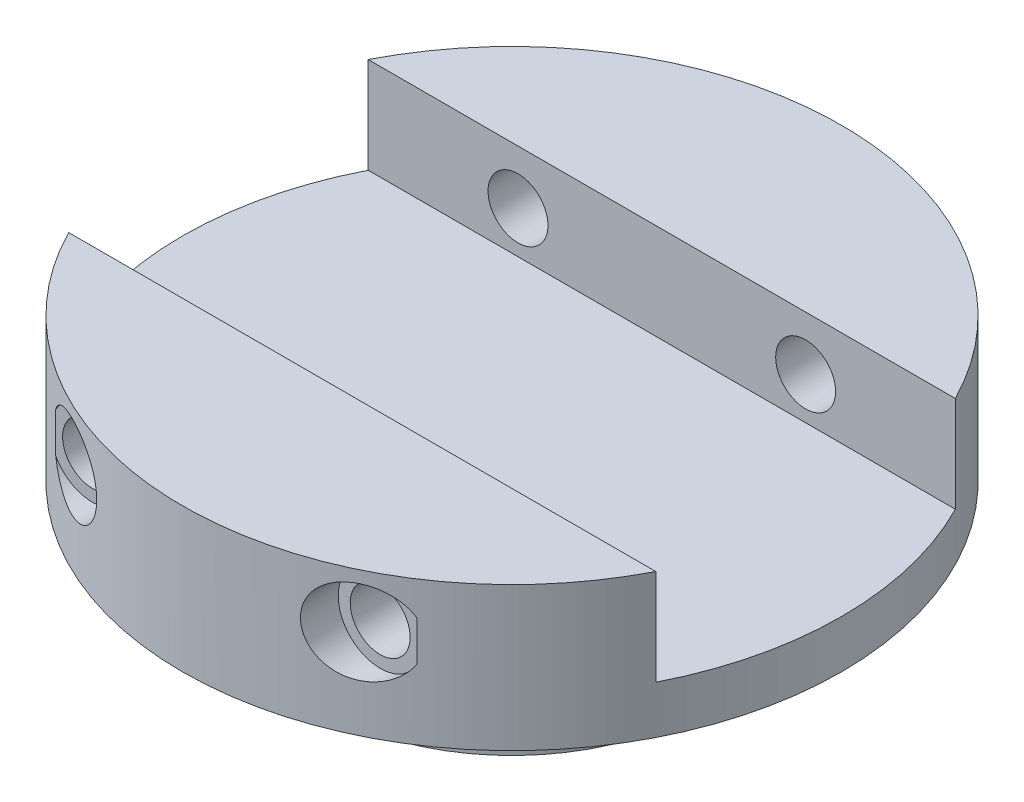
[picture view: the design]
ISO-10303-21;
HEADER;
FILE_DESCRIPTION(('STEP AP214'),'2;1');
FILE_NAME('part.step','',(''),(''),'','','');
FILE_SCHEMA(('AUTOMOTIVE_DESIGN { 1 0 10303 214 1 1 1 1 }'));
ENDSEC;
DATA;
#1=APPLICATION_CONTEXT('core data for automotive mechanical design processes');
#2=APPLICATION_PROTOCOL_DEFINITION('international standard','automotive_design',2000,#1);
#3=PRODUCT_CONTEXT('',#1,'mechanical');
#4=PRODUCT('Part','Part','',(#3));
#5=PRODUCT_RELATED_PRODUCT_CATEGORY('part','',(#4));
#6=PRODUCT_DEFINITION_FORMATION('','',#4);
#7=PRODUCT_DEFINITION_CONTEXT('part definition',#1,'design');
#8=PRODUCT_DEFINITION('design','',#6,#7);
#9=PRODUCT_DEFINITION_SHAPE('','',#8);
#10=(LENGTH_UNIT() NAMED_UNIT(*) SI_UNIT(.MILLI.,.METRE.));
#11=(NAMED_UNIT(*) PLANE_ANGLE_UNIT() SI_UNIT($,.RADIAN.));
#12=(NAMED_UNIT(*) SI_UNIT($,.STERADIAN.) SOLID_ANGLE_UNIT());
#13=UNCERTAINTY_MEASURE_WITH_UNIT(LENGTH_MEASURE(1.E-05),#10,'distance_accuracy_value','');
#14=(GEOMETRIC_REPRESENTATION_CONTEXT(3) GLOBAL_UNCERTAINTY_ASSIGNED_CONTEXT((#13)) GLOBAL_UNIT_ASSIGNED_CONTEXT((#10,
#11,#12)) REPRESENTATION_CONTEXT('',''));
#15=CARTESIAN_POINT('',(0.,0.,0.));
#16=DIRECTION('',(0.,0.,1.));
#17=DIRECTION('',(1.,0.,0.));
#18=AXIS2_PLACEMENT_3D('',#15,#16,#17);
#19=CARTESIAN_POINT('',(0.,19.05,0.));
#20=DIRECTION('',(0.,-1.,0.));
#21=DIRECTION('',(0.,0.,-1.));
#22=AXIS2_PLACEMENT_3D('',#19,#20,#21);
#23=CYLINDRICAL_SURFACE('',#22,43.65625);
#24=DIRECTION('',(0.,-1.,0.));
#25=VECTOR('',#24,1.);
#26=CARTESIAN_POINT('',(-23.9312663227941,19.05,-36.5125));
#27=LINE('',#26,#25);
#28=CARTESIAN_POINT('',(-23.9312663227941,9.25197926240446,-36.5125));
#29=VERTEX_POINT('',#28);
#30=CARTESIAN_POINT('',(-23.9312663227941,14.5605207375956,-36.5125));
#31=VERTEX_POINT('',#30);
#32=EDGE_CURVE('E121',#29,#31,#27,.F.);
#33=ORIENTED_EDGE('',*,*,#32,.F.);
#34=CARTESIAN_POINT('',(-23.9312663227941,9.25197926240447,-36.5125));
#35=CARTESIAN_POINT('',(-23.852149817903,9.10649225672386,-36.5643550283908));
#36=CARTESIAN_POINT('',(-23.7671347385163,8.96563827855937,-36.6197081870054));
#37=CARTESIAN_POINT('',(-23.5863859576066,8.69381280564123,-36.7363872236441));
#38=CARTESIAN_POINT('',(-23.4906623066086,8.56283223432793,-36.7977074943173));
#39=CARTESIAN_POINT('',(-23.1898679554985,8.18655993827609,-36.9885676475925));
#40=CARTESIAN_POINT('',(-22.9703170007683,7.9563920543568,-37.1255750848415));
#41=CARTESIAN_POINT('',(-22.5013637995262,7.54070185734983,-37.4116565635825));
#42=CARTESIAN_POINT('',(-22.2520689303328,7.35502581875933,-37.5606866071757));
#43=CARTESIAN_POINT('',(-21.7288893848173,7.02868923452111,-37.8657541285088));
#44=CARTESIAN_POINT('',(-21.4549682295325,6.88809692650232,-38.0218018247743));
#45=CARTESIAN_POINT('',(-20.8574448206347,6.64119424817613,-38.3531522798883));
#46=CARTESIAN_POINT('',(-20.5316948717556,6.54037308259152,-38.528680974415));
#47=CARTESIAN_POINT('',(-19.8653398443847,6.3996254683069,-38.8764367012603));
#48=CARTESIAN_POINT('',(-19.5247345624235,6.35969985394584,-39.0486636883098));
#49=CARTESIAN_POINT('',(-19.0052198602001,6.34737392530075,-39.3027821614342));
#50=CARTESIAN_POINT('',(-18.8281730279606,6.35158706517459,-39.3878986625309));
#51=CARTESIAN_POINT('',(-18.4739793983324,6.3770915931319,-39.5552586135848));
#52=CARTESIAN_POINT('',(-18.2968326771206,6.39837560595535,-39.6375032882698));
#53=CARTESIAN_POINT('',(-17.9438463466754,6.45827747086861,-39.7985454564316));
#54=CARTESIAN_POINT('',(-17.7680071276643,6.49690030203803,-39.8773419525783));
#55=CARTESIAN_POINT('',(-17.4193685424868,6.5915950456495,-40.0308631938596));
#56=CARTESIAN_POINT('',(-17.2465676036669,6.64765763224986,-40.1055900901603));
#57=CARTESIAN_POINT('',(-16.9162416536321,6.77319605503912,-40.2459827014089));
#58=CARTESIAN_POINT('',(-16.7584344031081,6.84162271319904,-40.3119229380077));
#59=CARTESIAN_POINT('',(-16.448512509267,6.99361875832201,-40.4393701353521));
#60=CARTESIAN_POINT('',(-16.2963950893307,7.07718063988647,-40.5008792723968));
#61=CARTESIAN_POINT('',(-15.9993741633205,7.25910905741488,-40.6191302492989));
#62=CARTESIAN_POINT('',(-15.8544689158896,7.35747199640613,-40.6758732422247));
#63=CARTESIAN_POINT('',(-15.5734291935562,7.56848128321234,-40.7843003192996));
#64=CARTESIAN_POINT('',(-15.4372939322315,7.68112634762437,-40.8359848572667));
#65=CARTESIAN_POINT('',(-15.1871935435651,7.90917059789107,-40.9296165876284));
#66=CARTESIAN_POINT('',(-15.0723362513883,8.02340507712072,-40.97202157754));
#67=CARTESIAN_POINT('',(-14.8523466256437,8.26235285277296,-41.052279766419));
#68=CARTESIAN_POINT('',(-14.7472134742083,8.38706526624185,-41.0901333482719));
#69=CARTESIAN_POINT('',(-14.547798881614,8.64606537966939,-41.1611578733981));
#70=CARTESIAN_POINT('',(-14.4535140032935,8.78035002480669,-41.1943303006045));
#71=CARTESIAN_POINT('',(-14.2767751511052,9.0575223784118,-41.2559161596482));
#72=CARTESIAN_POINT('',(-14.1943206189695,9.20040968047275,-41.2843298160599));
#73=CARTESIAN_POINT('',(-14.0473575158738,9.48361362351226,-41.3345560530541));
#74=CARTESIAN_POINT('',(-13.9820072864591,9.6234377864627,-41.3566871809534));
#75=CARTESIAN_POINT('',(-13.8629979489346,9.90855539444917,-41.3967317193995));
#76=CARTESIAN_POINT('',(-13.8093381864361,10.0538485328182,-41.4146453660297));
#77=CARTESIAN_POINT('',(-13.7142455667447,10.3488016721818,-41.4462319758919));
#78=CARTESIAN_POINT('',(-13.6728104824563,10.4984608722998,-41.4599057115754));
#79=CARTESIAN_POINT('',(-13.6025661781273,10.8010357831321,-41.4830052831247));
#80=CARTESIAN_POINT('',(-13.5737567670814,10.9539514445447,-41.4924311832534));
#81=CARTESIAN_POINT('',(-13.5298518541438,11.2563426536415,-41.5067679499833));
#82=CARTESIAN_POINT('',(-13.5143023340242,11.4057453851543,-41.5118283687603));
#83=CARTESIAN_POINT('',(-13.4953490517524,11.7054530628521,-41.5179939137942));
#84=CARTESIAN_POINT('',(-13.4919493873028,11.8557582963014,-41.5190977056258));
#85=CARTESIAN_POINT('',(-13.4973382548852,12.1560584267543,-41.5173461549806));
#86=CARTESIAN_POINT('',(-13.50612128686,12.3060534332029,-41.5144925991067));
#87=CARTESIAN_POINT('',(-13.5357892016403,12.604769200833,-41.5048288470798));
#88=CARTESIAN_POINT('',(-13.5566785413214,12.7534894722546,-41.4980171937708));
#89=CARTESIAN_POINT('',(-13.6100836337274,13.0469666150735,-41.4805323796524));
#90=CARTESIAN_POINT('',(-13.6424742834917,13.1917487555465,-41.4699007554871));
#91=CARTESIAN_POINT('',(-13.7186346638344,13.4780008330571,-41.4447684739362));
#92=CARTESIAN_POINT('',(-13.7624085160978,13.6194695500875,-41.4302664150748));
#93=CARTESIAN_POINT('',(-13.8609149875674,13.8980143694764,-41.3974140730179));
#94=CARTESIAN_POINT('',(-13.9156433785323,14.0350921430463,-41.3790652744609));
#95=CARTESIAN_POINT('',(-14.0356017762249,14.3040436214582,-41.3385298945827));
#96=CARTESIAN_POINT('',(-14.1008356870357,14.4359153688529,-41.3163418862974));
#97=CARTESIAN_POINT('',(-14.2419201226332,14.694840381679,-41.2679232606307));
#98=CARTESIAN_POINT('',(-14.3178707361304,14.821831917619,-41.2416542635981));
#99=CARTESIAN_POINT('',(-14.4792383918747,15.0688156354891,-41.1852779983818));
#100=CARTESIAN_POINT('',(-14.5646588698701,15.188805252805,-41.1551693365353));
#101=CARTESIAN_POINT('',(-14.7441756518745,15.420978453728,-41.091197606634));
#102=CARTESIAN_POINT('',(-14.8382692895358,15.5331644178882,-41.0573356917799));
#103=CARTESIAN_POINT('',(-15.034393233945,15.749179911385,-40.9859253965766));
#104=CARTESIAN_POINT('',(-15.1364265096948,15.8530062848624,-40.9483756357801));
#105=CARTESIAN_POINT('',(-15.3510355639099,16.0549828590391,-40.8684155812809));
#106=CARTESIAN_POINT('',(-15.4638471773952,16.1528357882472,-40.8258863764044));
#107=CARTESIAN_POINT('',(-15.6960831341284,16.3385517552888,-40.737165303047));
#108=CARTESIAN_POINT('',(-15.8155098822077,16.4264111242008,-40.6909720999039));
#109=CARTESIAN_POINT('',(-16.182235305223,16.674346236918,-40.5471586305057));
#110=CARTESIAN_POINT('',(-16.4381493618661,16.8189377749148,-40.44424169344));
#111=CARTESIAN_POINT('',(-16.980709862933,17.071999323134,-40.2195841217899));
#112=CARTESIAN_POINT('',(-17.268278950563,17.1777896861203,-40.0970855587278));
#113=CARTESIAN_POINT('',(-17.8520462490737,17.340278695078,-39.8406115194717));
#114=CARTESIAN_POINT('',(-18.1482475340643,17.3969596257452,-39.706631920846));
#115=CARTESIAN_POINT('',(-18.7662236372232,17.4646480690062,-39.4185548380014));
#116=CARTESIAN_POINT('',(-19.0881006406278,17.4715216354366,-39.2637088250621));
#117=CARTESIAN_POINT('',(-19.7251192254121,17.4305668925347,-38.9475858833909));
#118=CARTESIAN_POINT('',(-20.0402588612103,17.3827229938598,-38.7863071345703));
#119=CARTESIAN_POINT('',(-20.6809032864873,17.2287487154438,-38.4487907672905));
#120=CARTESIAN_POINT('',(-21.0052868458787,17.1183468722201,-38.2723708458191));
#121=CARTESIAN_POINT('',(-21.6304179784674,16.8388580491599,-37.9225720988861));
#122=CARTESIAN_POINT('',(-21.9311357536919,16.6696984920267,-37.7491973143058));
#123=CARTESIAN_POINT('',(-22.360718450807,16.3719415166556,-37.4952694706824));
#124=CARTESIAN_POINT('',(-22.5017904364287,16.2638781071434,-37.410734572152));
#125=CARTESIAN_POINT('',(-22.7742875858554,16.0334059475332,-37.2454735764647));
#126=CARTESIAN_POINT('',(-22.9057102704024,15.9109935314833,-37.16474846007));
#127=CARTESIAN_POINT('',(-23.1570581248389,15.652762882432,-37.0086566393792));
#128=CARTESIAN_POINT('',(-23.277021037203,15.5169918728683,-36.933272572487));
#129=CARTESIAN_POINT('',(-23.5044548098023,15.2323397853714,-36.7889504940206));
#130=CARTESIAN_POINT('',(-23.6119374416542,15.0834712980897,-36.7200064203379));
#131=CARTESIAN_POINT('',(-23.7510170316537,14.8689176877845,-36.6300351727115));
#132=CARTESIAN_POINT('',(-23.7885961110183,14.808442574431,-36.6056383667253));
#133=CARTESIAN_POINT('',(-23.8615761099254,14.6857707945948,-36.5581077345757));
#134=CARTESIAN_POINT('',(-23.8969785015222,14.623575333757,-36.5349730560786));
#135=CARTESIAN_POINT('',(-23.9312663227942,14.5605207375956,-36.5125));
#136=B_SPLINE_CURVE_WITH_KNOTS('',3,(#34,#35,#36,#37,#38,#39,#40,#41,#42,#43,#44,#45,#46,#47,
#48,#49,#50,#51,#52,#53,#54,#55,#56,#57,#58,#59,#60,#61,#62,#63,#64,#65,#66,#67,#68,#69,#70,#71,
#72,#73,#74,#75,#76,#77,#78,#79,#80,#81,#82,#83,#84,#85,#86,#87,#88,#89,#90,#91,#92,#93,#94,#95,
#96,#97,#98,#99,#100,#101,#102,#103,#104,#105,#106,#107,#108,#109,#110,#111,#112,#113,#114,#115,
#116,#117,#118,#119,#120,#121,#122,#123,#124,#125,#126,#127,#128,#129,#130,#131,#132,#133,#134,
#135),.UNSPECIFIED.,.F.,.F.,(4,2,2,2,2,2,2,2,2,2,2,2,2,2,2,2,2,2,2,2,2,2,2,2,2,2,2,2,2,2,2,2,2,
2,2,2,2,2,2,2,2,2,2,2,2,2,2,2,2,2,4),(0.,0.5201551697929,1.03982618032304,2.07367689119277,
3.10390226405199,4.13567968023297,5.28122182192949,6.42677965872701,7.01561551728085,
7.60419711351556,8.19294783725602,8.78138426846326,9.33327836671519,9.88489953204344,
10.4363868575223,10.9878246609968,11.4895275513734,11.9911882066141,12.4926894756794,
12.9941670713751,13.4613493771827,13.9285055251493,14.3955765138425,14.8626404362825,
15.3129841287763,15.7634796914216,16.2137719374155,16.6642300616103,17.1099314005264,
17.5557943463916,18.00148552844,18.447342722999,18.8976798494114,19.3481809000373,
19.79854391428,20.2490761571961,20.7143639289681,21.1798219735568,22.1100230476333,
23.0958939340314,24.0821203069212,25.1493536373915,26.2168911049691,27.3680368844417,
28.5206096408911,29.110319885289,29.7001811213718,30.2880273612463,30.8753145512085,
31.1010560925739,31.3266432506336),.UNSPECIFIED.);
#137=EDGE_CURVE('E45',#29,#31,#136,.T.);
#138=ORIENTED_EDGE('',*,*,#137,.T.);
#139=EDGE_LOOP('',(#33,#138));
#140=FACE_BOUND('',#139,.T.);
#141=DIRECTION('',(0.,-1.,0.));
#142=VECTOR('',#141,1.);
#143=CARTESIAN_POINT('',(23.9312663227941,19.05,36.5125));
#144=LINE('',#143,#142);
#145=CARTESIAN_POINT('',(23.9312663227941,9.25197926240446,36.5125));
#146=VERTEX_POINT('',#145);
#147=CARTESIAN_POINT('',(23.9312663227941,14.5605207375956,36.5125));
#148=VERTEX_POINT('',#147);
#149=EDGE_CURVE('E125',#146,#148,#144,.F.);
#150=ORIENTED_EDGE('',*,*,#149,.F.);
#151=CARTESIAN_POINT('',(23.9312663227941,9.25197926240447,36.5125));
#152=CARTESIAN_POINT('',(23.852149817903,9.10649225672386,36.5643550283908));
#153=CARTESIAN_POINT('',(23.7671347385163,8.96563827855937,36.6197081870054));
#154=CARTESIAN_POINT('',(23.5863859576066,8.69381280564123,36.7363872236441));
#155=CARTESIAN_POINT('',(23.4906623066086,8.56283223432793,36.7977074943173));
#156=CARTESIAN_POINT('',(23.1898679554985,8.18655993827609,36.9885676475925));
#157=CARTESIAN_POINT('',(22.9703170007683,7.9563920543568,37.1255750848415));
#158=CARTESIAN_POINT('',(22.5013637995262,7.54070185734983,37.4116565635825));
#159=CARTESIAN_POINT('',(22.2520689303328,7.35502581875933,37.5606866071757));
#160=CARTESIAN_POINT('',(21.7288893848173,7.02868923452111,37.8657541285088));
#161=CARTESIAN_POINT('',(21.4549682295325,6.88809692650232,38.0218018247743));
#162=CARTESIAN_POINT('',(20.8574448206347,6.64119424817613,38.3531522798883));
#163=CARTESIAN_POINT('',(20.5316948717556,6.54037308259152,38.528680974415));
#164=CARTESIAN_POINT('',(19.8653398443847,6.3996254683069,38.8764367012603));
#165=CARTESIAN_POINT('',(19.5247345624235,6.35969985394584,39.0486636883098));
#166=CARTESIAN_POINT('',(19.0052198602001,6.34737392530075,39.3027821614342));
#167=CARTESIAN_POINT('',(18.8281730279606,6.35158706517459,39.3878986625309));
#168=CARTESIAN_POINT('',(18.4739793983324,6.3770915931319,39.5552586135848));
#169=CARTESIAN_POINT('',(18.2968326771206,6.39837560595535,39.6375032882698));
#170=CARTESIAN_POINT('',(17.9438463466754,6.45827747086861,39.7985454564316));
#171=CARTESIAN_POINT('',(17.7680071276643,6.49690030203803,39.8773419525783));
#172=CARTESIAN_POINT('',(17.4193685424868,6.5915950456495,40.0308631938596));
#173=CARTESIAN_POINT('',(17.2465676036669,6.64765763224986,40.1055900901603));
#174=CARTESIAN_POINT('',(16.9162416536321,6.77319605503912,40.2459827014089));
#175=CARTESIAN_POINT('',(16.7584344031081,6.84162271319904,40.3119229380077));
#176=CARTESIAN_POINT('',(16.448512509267,6.99361875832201,40.4393701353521));
#177=CARTESIAN_POINT('',(16.2963950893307,7.07718063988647,40.5008792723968));
#178=CARTESIAN_POINT('',(15.9993741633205,7.25910905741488,40.6191302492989));
#179=CARTESIAN_POINT('',(15.8544689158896,7.35747199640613,40.6758732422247));
#180=CARTESIAN_POINT('',(15.5734291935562,7.56848128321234,40.7843003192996));
#181=CARTESIAN_POINT('',(15.4372939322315,7.68112634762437,40.8359848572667));
#182=CARTESIAN_POINT('',(15.1871935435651,7.90917059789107,40.9296165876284));
#183=CARTESIAN_POINT('',(15.0723362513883,8.02340507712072,40.97202157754));
#184=CARTESIAN_POINT('',(14.8523466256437,8.26235285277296,41.052279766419));
#185=CARTESIAN_POINT('',(14.7472134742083,8.38706526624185,41.0901333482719));
#186=CARTESIAN_POINT('',(14.547798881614,8.64606537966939,41.1611578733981));
#187=CARTESIAN_POINT('',(14.4535140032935,8.78035002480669,41.1943303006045));
#188=CARTESIAN_POINT('',(14.2767751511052,9.0575223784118,41.2559161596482));
#189=CARTESIAN_POINT('',(14.1943206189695,9.20040968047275,41.2843298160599));
#190=CARTESIAN_POINT('',(14.0473575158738,9.48361362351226,41.3345560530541));
#191=CARTESIAN_POINT('',(13.9820072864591,9.6234377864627,41.3566871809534));
#192=CARTESIAN_POINT('',(13.8629979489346,9.90855539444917,41.3967317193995));
#193=CARTESIAN_POINT('',(13.8093381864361,10.0538485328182,41.4146453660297));
#194=CARTESIAN_POINT('',(13.7142455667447,10.3488016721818,41.4462319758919));
#195=CARTESIAN_POINT('',(13.6728104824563,10.4984608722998,41.4599057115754));
#196=CARTESIAN_POINT('',(13.6025661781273,10.8010357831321,41.4830052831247));
#197=CARTESIAN_POINT('',(13.5737567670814,10.9539514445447,41.4924311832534));
#198=CARTESIAN_POINT('',(13.5298518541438,11.2563426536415,41.5067679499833));
#199=CARTESIAN_POINT('',(13.5143023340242,11.4057453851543,41.5118283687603));
#200=CARTESIAN_POINT('',(13.4953490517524,11.7054530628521,41.5179939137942));
#201=CARTESIAN_POINT('',(13.4919493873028,11.8557582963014,41.5190977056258));
#202=CARTESIAN_POINT('',(13.4973382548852,12.1560584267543,41.5173461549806));
#203=CARTESIAN_POINT('',(13.50612128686,12.3060534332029,41.5144925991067));
#204=CARTESIAN_POINT('',(13.5357892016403,12.604769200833,41.5048288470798));
#205=CARTESIAN_POINT('',(13.5566785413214,12.7534894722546,41.4980171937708));
#206=CARTESIAN_POINT('',(13.6100836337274,13.0469666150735,41.4805323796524));
#207=CARTESIAN_POINT('',(13.6424742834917,13.1917487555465,41.4699007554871));
#208=CARTESIAN_POINT('',(13.7186346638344,13.4780008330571,41.4447684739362));
#209=CARTESIAN_POINT('',(13.7624085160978,13.6194695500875,41.4302664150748));
#210=CARTESIAN_POINT('',(13.8609149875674,13.8980143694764,41.3974140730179));
#211=CARTESIAN_POINT('',(13.9156433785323,14.0350921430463,41.3790652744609));
#212=CARTESIAN_POINT('',(14.0356017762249,14.3040436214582,41.3385298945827));
#213=CARTESIAN_POINT('',(14.1008356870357,14.4359153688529,41.3163418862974));
#214=CARTESIAN_POINT('',(14.2419201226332,14.694840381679,41.2679232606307));
#215=CARTESIAN_POINT('',(14.3178707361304,14.821831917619,41.2416542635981));
#216=CARTESIAN_POINT('',(14.4792383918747,15.0688156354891,41.1852779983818));
#217=CARTESIAN_POINT('',(14.5646588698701,15.188805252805,41.1551693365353));
#218=CARTESIAN_POINT('',(14.7441756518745,15.420978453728,41.091197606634));
#219=CARTESIAN_POINT('',(14.8382692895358,15.5331644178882,41.0573356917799));
#220=CARTESIAN_POINT('',(15.034393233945,15.749179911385,40.9859253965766));
#221=CARTESIAN_POINT('',(15.1364265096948,15.8530062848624,40.9483756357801));
#222=CARTESIAN_POINT('',(15.3510355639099,16.0549828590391,40.8684155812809));
#223=CARTESIAN_POINT('',(15.4638471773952,16.1528357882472,40.8258863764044));
#224=CARTESIAN_POINT('',(15.6960831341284,16.3385517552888,40.737165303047));
#225=CARTESIAN_POINT('',(15.8155098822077,16.4264111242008,40.6909720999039));
#226=CARTESIAN_POINT('',(16.182235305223,16.674346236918,40.5471586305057));
#227=CARTESIAN_POINT('',(16.4381493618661,16.8189377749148,40.44424169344));
#228=CARTESIAN_POINT('',(16.980709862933,17.071999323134,40.2195841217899));
#229=CARTESIAN_POINT('',(17.268278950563,17.1777896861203,40.0970855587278));
#230=CARTESIAN_POINT('',(17.8520462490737,17.340278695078,39.8406115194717));
#231=CARTESIAN_POINT('',(18.1482475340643,17.3969596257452,39.706631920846));
#232=CARTESIAN_POINT('',(18.7662236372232,17.4646480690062,39.4185548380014));
#233=CARTESIAN_POINT('',(19.0881006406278,17.4715216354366,39.2637088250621));
#234=CARTESIAN_POINT('',(19.7251192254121,17.4305668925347,38.9475858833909));
#235=CARTESIAN_POINT('',(20.0402588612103,17.3827229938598,38.7863071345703));
#236=CARTESIAN_POINT('',(20.6809032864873,17.2287487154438,38.4487907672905));
#237=CARTESIAN_POINT('',(21.0052868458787,17.1183468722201,38.2723708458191));
#238=CARTESIAN_POINT('',(21.6304179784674,16.8388580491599,37.9225720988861));
#239=CARTESIAN_POINT('',(21.9311357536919,16.6696984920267,37.7491973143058));
#240=CARTESIAN_POINT('',(22.360718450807,16.3719415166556,37.4952694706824));
#241=CARTESIAN_POINT('',(22.5017904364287,16.2638781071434,37.410734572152));
#242=CARTESIAN_POINT('',(22.7742875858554,16.0334059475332,37.2454735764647));
#243=CARTESIAN_POINT('',(22.9057102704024,15.9109935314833,37.16474846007));
#244=CARTESIAN_POINT('',(23.1570581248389,15.652762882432,37.0086566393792));
#245=CARTESIAN_POINT('',(23.277021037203,15.5169918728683,36.933272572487));
#246=CARTESIAN_POINT('',(23.5044548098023,15.2323397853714,36.7889504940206));
#247=CARTESIAN_POINT('',(23.6119374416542,15.0834712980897,36.7200064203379));
#248=CARTESIAN_POINT('',(23.7510170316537,14.8689176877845,36.6300351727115));
#249=CARTESIAN_POINT('',(23.7885961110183,14.808442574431,36.6056383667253));
#250=CARTESIAN_POINT('',(23.8615761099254,14.6857707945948,36.5581077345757));
#251=CARTESIAN_POINT('',(23.8969785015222,14.623575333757,36.5349730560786));
#252=CARTESIAN_POINT('',(23.9312663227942,14.5605207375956,36.5125));
#253=B_SPLINE_CURVE_WITH_KNOTS('',3,(#151,#152,#153,#154,#155,#156,#157,#158,#159,#160,#161,
#162,#163,#164,#165,#166,#167,#168,#169,#170,#171,#172,#173,#174,#175,#176,#177,#178,#179,#180,
#181,#182,#183,#184,#185,#186,#187,#188,#189,#190,#191,#192,#193,#194,#195,#196,#197,#198,#199,
#200,#201,#202,#203,#204,#205,#206,#207,#208,#209,#210,#211,#212,#213,#214,#215,#216,#217,#218,
#219,#220,#221,#222,#223,#224,#225,#226,#227,#228,#229,#230,#231,#232,#233,#234,#235,#236,#237,
#238,#239,#240,#241,#242,#243,#244,#245,#246,#247,#248,#249,#250,#251,#252),.UNSPECIFIED.,.F.,
.F.,(4,2,2,2,2,2,2,2,2,2,2,2,2,2,2,2,2,2,2,2,2,2,2,2,2,2,2,2,2,2,2,2,2,2,2,2,2,2,2,2,2,2,2,2,2,
2,2,2,2,2,4),(0.,0.5201551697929,1.03982618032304,2.07367689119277,3.10390226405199,
4.13567968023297,5.28122182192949,6.42677965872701,7.01561551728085,7.60419711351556,
8.19294783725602,8.78138426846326,9.33327836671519,9.88489953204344,10.4363868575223,
10.9878246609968,11.4895275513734,11.9911882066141,12.4926894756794,12.9941670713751,
13.4613493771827,13.9285055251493,14.3955765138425,14.8626404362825,15.3129841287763,
15.7634796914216,16.2137719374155,16.6642300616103,17.1099314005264,17.5557943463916,
18.00148552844,18.447342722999,18.8976798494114,19.3481809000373,19.79854391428,
20.2490761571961,20.7143639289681,21.1798219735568,22.1100230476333,23.0958939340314,
24.0821203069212,25.1493536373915,26.2168911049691,27.3680368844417,28.5206096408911,
29.110319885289,29.7001811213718,30.2880273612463,30.8753145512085,31.1010560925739,
31.3266432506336),.UNSPECIFIED.);
#254=EDGE_CURVE('E142',#146,#148,#253,.T.);
#255=ORIENTED_EDGE('',*,*,#254,.T.);
#256=EDGE_LOOP('',(#150,#255));
#257=FACE_BOUND('',#256,.T.);
#258=CARTESIAN_POINT('',(0.,6.35,0.));
#259=DIRECTION('',(0.,1.,0.));
#260=DIRECTION('',(0.,0.,1.));
#261=AXIS2_PLACEMENT_3D('',#258,#259,#260);
#262=CIRCLE('',#261,43.65625);
#263=CARTESIAN_POINT('',(38.885649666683,6.35,19.84375));
#264=VERTEX_POINT('',#263);
#265=CARTESIAN_POINT('',(38.885649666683,6.35,-19.84375));
#266=VERTEX_POINT('',#265);
#267=EDGE_CURVE('E129',#264,#266,#262,.T.);
#268=ORIENTED_EDGE('',*,*,#267,.F.);
#269=DIRECTION('',(0.,-1.,0.));
#270=VECTOR('',#269,1.);
#271=CARTESIAN_POINT('',(38.8856496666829,19.05,19.84375));
#272=LINE('',#271,#270);
#273=CARTESIAN_POINT('',(38.885649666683,19.05,19.84375));
#274=VERTEX_POINT('',#273);
#275=EDGE_CURVE('E237',#264,#274,#272,.F.);
#276=ORIENTED_EDGE('',*,*,#275,.T.);
#277=CARTESIAN_POINT('',(0.,19.05,0.));
#278=DIRECTION('',(0.,1.,0.));
#279=DIRECTION('',(0.,0.,1.));
#280=AXIS2_PLACEMENT_3D('',#277,#278,#279);
#281=CIRCLE('',#280,43.65625);
#282=CARTESIAN_POINT('',(-38.885649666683,19.05,19.84375));
#283=VERTEX_POINT('',#282);
#284=EDGE_CURVE('E212',#283,#274,#281,.T.);
#285=ORIENTED_EDGE('',*,*,#284,.F.);
#286=DIRECTION('',(0.,-1.,0.));
#287=VECTOR('',#286,1.);
#288=CARTESIAN_POINT('',(-38.8856496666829,19.05,19.84375));
#289=LINE('',#288,#287);
#290=CARTESIAN_POINT('',(-38.885649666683,6.35,19.84375));
#291=VERTEX_POINT('',#290);
#292=EDGE_CURVE('E239',#283,#291,#289,.T.);
#293=ORIENTED_EDGE('',*,*,#292,.T.);
#294=CARTESIAN_POINT('',(-38.885649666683,6.35,-19.84375));
#295=VERTEX_POINT('',#294);
#296=EDGE_CURVE('E143',#295,#291,#262,.T.);
#297=ORIENTED_EDGE('',*,*,#296,.F.);
#298=DIRECTION('',(0.,-1.,0.));
#299=VECTOR('',#298,1.);
#300=CARTESIAN_POINT('',(-38.8856496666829,19.05,-19.84375));
#301=LINE('',#300,#299);
#302=CARTESIAN_POINT('',(-38.885649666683,19.05,-19.84375));
#303=VERTEX_POINT('',#302);
#304=EDGE_CURVE('E231',#295,#303,#301,.F.);
#305=ORIENTED_EDGE('',*,*,#304,.T.);
#306=CARTESIAN_POINT('',(38.885649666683,19.05,-19.84375));
#307=VERTEX_POINT('',#306);
#308=EDGE_CURVE('E207',#307,#303,#281,.T.);
#309=ORIENTED_EDGE('',*,*,#308,.F.);
#310=DIRECTION('',(0.,-1.,0.));
#311=VECTOR('',#310,1.);
#312=CARTESIAN_POINT('',(38.8856496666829,19.05,-19.84375));
#313=LINE('',#312,#311);
#314=EDGE_CURVE('E235',#307,#266,#313,.T.);
#315=ORIENTED_EDGE('',*,*,#314,.T.);
#316=EDGE_LOOP('',(#268,#276,#285,#293,#297,#305,#309,#315));
#317=FACE_BOUND('',#316,.T.);
#318=CARTESIAN_POINT('',(0.,0.,0.));
#319=DIRECTION('',(0.,1.,0.));
#320=DIRECTION('',(0.,0.,1.));
#321=AXIS2_PLACEMENT_3D('',#318,#319,#320);
#322=CIRCLE('',#321,43.65625);
#323=CARTESIAN_POINT('',(0.,0.,43.65625));
#324=VERTEX_POINT('',#323);
#325=EDGE_CURVE('E134',#324,#324,#322,.T.);
#326=ORIENTED_EDGE('',*,*,#325,.T.);
#327=EDGE_LOOP('',(#326));
#328=FACE_BOUND('',#327,.T.);
#329=CARTESIAN_POINT('',(-23.9312663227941,9.25197926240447,36.5125));
#330=CARTESIAN_POINT('',(-23.852149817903,9.10649225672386,36.5643550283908));
#331=CARTESIAN_POINT('',(-23.7671347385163,8.96563827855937,36.6197081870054));
#332=CARTESIAN_POINT('',(-23.5863859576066,8.69381280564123,36.7363872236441));
#333=CARTESIAN_POINT('',(-23.4906623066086,8.56283223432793,36.7977074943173));
#334=CARTESIAN_POINT('',(-23.1898679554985,8.18655993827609,36.9885676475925));
#335=CARTESIAN_POINT('',(-22.9703170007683,7.9563920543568,37.1255750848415));
#336=CARTESIAN_POINT('',(-22.5013637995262,7.54070185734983,37.4116565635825));
#337=CARTESIAN_POINT('',(-22.2520689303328,7.35502581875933,37.5606866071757));
#338=CARTESIAN_POINT('',(-21.7288893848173,7.02868923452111,37.8657541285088));
#339=CARTESIAN_POINT('',(-21.4549682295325,6.88809692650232,38.0218018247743));
#340=CARTESIAN_POINT('',(-20.8574448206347,6.64119424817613,38.3531522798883));
#341=CARTESIAN_POINT('',(-20.5316948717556,6.54037308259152,38.528680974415));
#342=CARTESIAN_POINT('',(-19.8653398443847,6.3996254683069,38.8764367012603));
#343=CARTESIAN_POINT('',(-19.5247345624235,6.35969985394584,39.0486636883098));
#344=CARTESIAN_POINT('',(-19.0052198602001,6.34737392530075,39.3027821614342));
#345=CARTESIAN_POINT('',(-18.8281730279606,6.35158706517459,39.3878986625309));
#346=CARTESIAN_POINT('',(-18.4739793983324,6.3770915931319,39.5552586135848));
#347=CARTESIAN_POINT('',(-18.2968326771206,6.39837560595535,39.6375032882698));
#348=CARTESIAN_POINT('',(-17.9438463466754,6.45827747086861,39.7985454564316));
#349=CARTESIAN_POINT('',(-17.7680071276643,6.49690030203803,39.8773419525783));
#350=CARTESIAN_POINT('',(-17.4193685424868,6.5915950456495,40.0308631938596));
#351=CARTESIAN_POINT('',(-17.2465676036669,6.64765763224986,40.1055900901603));
#352=CARTESIAN_POINT('',(-16.9162416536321,6.77319605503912,40.2459827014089));
#353=CARTESIAN_POINT('',(-16.7584344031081,6.84162271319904,40.3119229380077));
#354=CARTESIAN_POINT('',(-16.448512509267,6.99361875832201,40.4393701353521));
#355=CARTESIAN_POINT('',(-16.2963950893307,7.07718063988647,40.5008792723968));
#356=CARTESIAN_POINT('',(-15.9993741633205,7.25910905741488,40.6191302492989));
#357=CARTESIAN_POINT('',(-15.8544689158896,7.35747199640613,40.6758732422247));
#358=CARTESIAN_POINT('',(-15.5734291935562,7.56848128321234,40.7843003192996));
#359=CARTESIAN_POINT('',(-15.4372939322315,7.68112634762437,40.8359848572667));
#360=CARTESIAN_POINT('',(-15.1871935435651,7.90917059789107,40.9296165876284));
#361=CARTESIAN_POINT('',(-15.0723362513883,8.02340507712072,40.97202157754));
#362=CARTESIAN_POINT('',(-14.8523466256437,8.26235285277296,41.052279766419));
#363=CARTESIAN_POINT('',(-14.7472134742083,8.38706526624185,41.0901333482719));
#364=CARTESIAN_POINT('',(-14.547798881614,8.64606537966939,41.1611578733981));
#365=CARTESIAN_POINT('',(-14.4535140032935,8.78035002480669,41.1943303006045));
#366=CARTESIAN_POINT('',(-14.2767751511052,9.0575223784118,41.2559161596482));
#367=CARTESIAN_POINT('',(-14.1943206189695,9.20040968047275,41.2843298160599));
#368=CARTESIAN_POINT('',(-14.0473575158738,9.48361362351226,41.3345560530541));
#369=CARTESIAN_POINT('',(-13.9820072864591,9.6234377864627,41.3566871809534));
#370=CARTESIAN_POINT('',(-13.8629979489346,9.90855539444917,41.3967317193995));
#371=CARTESIAN_POINT('',(-13.8093381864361,10.0538485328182,41.4146453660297));
#372=CARTESIAN_POINT('',(-13.7142455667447,10.3488016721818,41.4462319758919));
#373=CARTESIAN_POINT('',(-13.6728104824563,10.4984608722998,41.4599057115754));
#374=CARTESIAN_POINT('',(-13.6025661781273,10.8010357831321,41.4830052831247));
#375=CARTESIAN_POINT('',(-13.5737567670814,10.9539514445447,41.4924311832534));
#376=CARTESIAN_POINT('',(-13.5298518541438,11.2563426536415,41.5067679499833));
#377=CARTESIAN_POINT('',(-13.5143023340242,11.4057453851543,41.5118283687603));
#378=CARTESIAN_POINT('',(-13.4953490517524,11.7054530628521,41.5179939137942));
#379=CARTESIAN_POINT('',(-13.4919493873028,11.8557582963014,41.5190977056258));
#380=CARTESIAN_POINT('',(-13.4973382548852,12.1560584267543,41.5173461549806));
#381=CARTESIAN_POINT('',(-13.50612128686,12.3060534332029,41.5144925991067));
#382=CARTESIAN_POINT('',(-13.5357892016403,12.604769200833,41.5048288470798));
#383=CARTESIAN_POINT('',(-13.5566785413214,12.7534894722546,41.4980171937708));
#384=CARTESIAN_POINT('',(-13.6100836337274,13.0469666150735,41.4805323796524));
#385=CARTESIAN_POINT('',(-13.6424742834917,13.1917487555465,41.4699007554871));
#386=CARTESIAN_POINT('',(-13.7186346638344,13.4780008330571,41.4447684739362));
#387=CARTESIAN_POINT('',(-13.7624085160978,13.6194695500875,41.4302664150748));
#388=CARTESIAN_POINT('',(-13.8609149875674,13.8980143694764,41.3974140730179));
#389=CARTESIAN_POINT('',(-13.9156433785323,14.0350921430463,41.3790652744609));
#390=CARTESIAN_POINT('',(-14.0356017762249,14.3040436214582,41.3385298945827));
#391=CARTESIAN_POINT('',(-14.1008356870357,14.4359153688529,41.3163418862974));
#392=CARTESIAN_POINT('',(-14.2419201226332,14.694840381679,41.2679232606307));
#393=CARTESIAN_POINT('',(-14.3178707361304,14.821831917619,41.2416542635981));
#394=CARTESIAN_POINT('',(-14.4792383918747,15.0688156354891,41.1852779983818));
#395=CARTESIAN_POINT('',(-14.5646588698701,15.188805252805,41.1551693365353));
#396=CARTESIAN_POINT('',(-14.7441756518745,15.420978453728,41.091197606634));
#397=CARTESIAN_POINT('',(-14.8382692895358,15.5331644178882,41.0573356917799));
#398=CARTESIAN_POINT('',(-15.034393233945,15.749179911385,40.9859253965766));
#399=CARTESIAN_POINT('',(-15.1364265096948,15.8530062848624,40.9483756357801));
#400=CARTESIAN_POINT('',(-15.3510355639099,16.0549828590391,40.8684155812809));
#401=CARTESIAN_POINT('',(-15.4638471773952,16.1528357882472,40.8258863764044));
#402=CARTESIAN_POINT('',(-15.6960831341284,16.3385517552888,40.737165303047));
#403=CARTESIAN_POINT('',(-15.8155098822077,16.4264111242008,40.6909720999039));
#404=CARTESIAN_POINT('',(-16.182235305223,16.674346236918,40.5471586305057));
#405=CARTESIAN_POINT('',(-16.4381493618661,16.8189377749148,40.44424169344));
#406=CARTESIAN_POINT('',(-16.980709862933,17.071999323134,40.2195841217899));
#407=CARTESIAN_POINT('',(-17.268278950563,17.1777896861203,40.0970855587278));
#408=CARTESIAN_POINT('',(-17.8520462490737,17.340278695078,39.8406115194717));
#409=CARTESIAN_POINT('',(-18.1482475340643,17.3969596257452,39.706631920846));
#410=CARTESIAN_POINT('',(-18.7662236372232,17.4646480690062,39.4185548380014));
#411=CARTESIAN_POINT('',(-19.0881006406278,17.4715216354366,39.2637088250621));
#412=CARTESIAN_POINT('',(-19.7251192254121,17.4305668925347,38.9475858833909));
#413=CARTESIAN_POINT('',(-20.0402588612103,17.3827229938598,38.7863071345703));
#414=CARTESIAN_POINT('',(-20.6809032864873,17.2287487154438,38.4487907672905));
#415=CARTESIAN_POINT('',(-21.0052868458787,17.1183468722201,38.2723708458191));
#416=CARTESIAN_POINT('',(-21.6304179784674,16.8388580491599,37.9225720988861));
#417=CARTESIAN_POINT('',(-21.9311357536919,16.6696984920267,37.7491973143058));
#418=CARTESIAN_POINT('',(-22.360718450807,16.3719415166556,37.4952694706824));
#419=CARTESIAN_POINT('',(-22.5017904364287,16.2638781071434,37.410734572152));
#420=CARTESIAN_POINT('',(-22.7742875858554,16.0334059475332,37.2454735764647));
#421=CARTESIAN_POINT('',(-22.9057102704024,15.9109935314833,37.16474846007));
#422=CARTESIAN_POINT('',(-23.1570581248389,15.652762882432,37.0086566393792));
#423=CARTESIAN_POINT('',(-23.277021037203,15.5169918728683,36.933272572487));
#424=CARTESIAN_POINT('',(-23.5044548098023,15.2323397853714,36.7889504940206));
#425=CARTESIAN_POINT('',(-23.6119374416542,15.0834712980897,36.7200064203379));
#426=CARTESIAN_POINT('',(-23.7510170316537,14.8689176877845,36.6300351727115));
#427=CARTESIAN_POINT('',(-23.7885961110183,14.808442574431,36.6056383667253));
#428=CARTESIAN_POINT('',(-23.8615761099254,14.6857707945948,36.5581077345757));
#429=CARTESIAN_POINT('',(-23.8969785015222,14.623575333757,36.5349730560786));
#430=CARTESIAN_POINT('',(-23.9312663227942,14.5605207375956,36.5125));
#431=B_SPLINE_CURVE_WITH_KNOTS('',3,(#329,#330,#331,#332,#333,#334,#335,#336,#337,#338,#339,
#340,#341,#342,#343,#344,#345,#346,#347,#348,#349,#350,#351,#352,#353,#354,#355,#356,#357,#358,
#359,#360,#361,#362,#363,#364,#365,#366,#367,#368,#369,#370,#371,#372,#373,#374,#375,#376,#377,
#378,#379,#380,#381,#382,#383,#384,#385,#386,#387,#388,#389,#390,#391,#392,#393,#394,#395,#396,
#397,#398,#399,#400,#401,#402,#403,#404,#405,#406,#407,#408,#409,#410,#411,#412,#413,#414,#415,
#416,#417,#418,#419,#420,#421,#422,#423,#424,#425,#426,#427,#428,#429,#430),.UNSPECIFIED.,.F.,
.F.,(4,2,2,2,2,2,2,2,2,2,2,2,2,2,2,2,2,2,2,2,2,2,2,2,2,2,2,2,2,2,2,2,2,2,2,2,2,2,2,2,2,2,2,2,2,
2,2,2,2,2,4),(0.,0.5201551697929,1.03982618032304,2.07367689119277,3.10390226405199,
4.13567968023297,5.28122182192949,6.42677965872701,7.01561551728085,7.60419711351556,
8.19294783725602,8.78138426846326,9.33327836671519,9.88489953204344,10.4363868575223,
10.9878246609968,11.4895275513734,11.9911882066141,12.4926894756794,12.9941670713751,
13.4613493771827,13.9285055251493,14.3955765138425,14.8626404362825,15.3129841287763,
15.7634796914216,16.2137719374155,16.6642300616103,17.1099314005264,17.5557943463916,
18.00148552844,18.447342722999,18.8976798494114,19.3481809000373,19.79854391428,
20.2490761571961,20.7143639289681,21.1798219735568,22.1100230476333,23.0958939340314,
24.0821203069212,25.1493536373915,26.2168911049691,27.3680368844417,28.5206096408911,
29.110319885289,29.7001811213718,30.2880273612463,30.8753145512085,31.1010560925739,
31.3266432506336),.UNSPECIFIED.);
#432=CARTESIAN_POINT('',(-23.9312663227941,9.25197926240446,36.5125));
#433=VERTEX_POINT('',#432);
#434=CARTESIAN_POINT('',(-23.9312663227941,14.5605207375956,36.5125));
#435=VERTEX_POINT('',#434);
#436=EDGE_CURVE('E138',#433,#435,#431,.T.);
#437=ORIENTED_EDGE('',*,*,#436,.F.);
#438=DIRECTION('',(0.,-1.,0.));
#439=VECTOR('',#438,1.);
#440=CARTESIAN_POINT('',(-23.9312663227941,19.05,36.5125));
#441=LINE('',#440,#439);
#442=EDGE_CURVE('E139',#435,#433,#441,.T.);
#443=ORIENTED_EDGE('',*,*,#442,.F.);
#444=EDGE_LOOP('',(#437,#443));
#445=FACE_BOUND('',#444,.T.);
#446=CARTESIAN_POINT('',(23.9312663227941,9.25197926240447,-36.5125));
#447=CARTESIAN_POINT('',(23.852149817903,9.10649225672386,-36.5643550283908));
#448=CARTESIAN_POINT('',(23.7671347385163,8.96563827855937,-36.6197081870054));
#449=CARTESIAN_POINT('',(23.5863859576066,8.69381280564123,-36.7363872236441));
#450=CARTESIAN_POINT('',(23.4906623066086,8.56283223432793,-36.7977074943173));
#451=CARTESIAN_POINT('',(23.1898679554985,8.18655993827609,-36.9885676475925));
#452=CARTESIAN_POINT('',(22.9703170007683,7.9563920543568,-37.1255750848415));
#453=CARTESIAN_POINT('',(22.5013637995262,7.54070185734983,-37.4116565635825));
#454=CARTESIAN_POINT('',(22.2520689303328,7.35502581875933,-37.5606866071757));
#455=CARTESIAN_POINT('',(21.7288893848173,7.02868923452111,-37.8657541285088));
#456=CARTESIAN_POINT('',(21.4549682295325,6.88809692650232,-38.0218018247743));
#457=CARTESIAN_POINT('',(20.8574448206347,6.64119424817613,-38.3531522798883));
#458=CARTESIAN_POINT('',(20.5316948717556,6.54037308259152,-38.528680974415));
#459=CARTESIAN_POINT('',(19.8653398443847,6.3996254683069,-38.8764367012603));
#460=CARTESIAN_POINT('',(19.5247345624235,6.35969985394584,-39.0486636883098));
#461=CARTESIAN_POINT('',(19.0052198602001,6.34737392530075,-39.3027821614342));
#462=CARTESIAN_POINT('',(18.8281730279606,6.35158706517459,-39.3878986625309));
#463=CARTESIAN_POINT('',(18.4739793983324,6.3770915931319,-39.5552586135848));
#464=CARTESIAN_POINT('',(18.2968326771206,6.39837560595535,-39.6375032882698));
#465=CARTESIAN_POINT('',(17.9438463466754,6.45827747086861,-39.7985454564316));
#466=CARTESIAN_POINT('',(17.7680071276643,6.49690030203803,-39.8773419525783));
#467=CARTESIAN_POINT('',(17.4193685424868,6.5915950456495,-40.0308631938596));
#468=CARTESIAN_POINT('',(17.2465676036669,6.64765763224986,-40.1055900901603));
#469=CARTESIAN_POINT('',(16.9162416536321,6.77319605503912,-40.2459827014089));
#470=CARTESIAN_POINT('',(16.7584344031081,6.84162271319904,-40.3119229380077));
#471=CARTESIAN_POINT('',(16.448512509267,6.99361875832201,-40.4393701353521));
#472=CARTESIAN_POINT('',(16.2963950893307,7.07718063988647,-40.5008792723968));
#473=CARTESIAN_POINT('',(15.9993741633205,7.25910905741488,-40.6191302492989));
#474=CARTESIAN_POINT('',(15.8544689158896,7.35747199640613,-40.6758732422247));
#475=CARTESIAN_POINT('',(15.5734291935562,7.56848128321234,-40.7843003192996));
#476=CARTESIAN_POINT('',(15.4372939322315,7.68112634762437,-40.8359848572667));
#477=CARTESIAN_POINT('',(15.1871935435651,7.90917059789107,-40.9296165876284));
#478=CARTESIAN_POINT('',(15.0723362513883,8.02340507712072,-40.97202157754));
#479=CARTESIAN_POINT('',(14.8523466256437,8.26235285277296,-41.052279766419));
#480=CARTESIAN_POINT('',(14.7472134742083,8.38706526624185,-41.0901333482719));
#481=CARTESIAN_POINT('',(14.547798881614,8.64606537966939,-41.1611578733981));
#482=CARTESIAN_POINT('',(14.4535140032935,8.78035002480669,-41.1943303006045));
#483=CARTESIAN_POINT('',(14.2767751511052,9.0575223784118,-41.2559161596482));
#484=CARTESIAN_POINT('',(14.1943206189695,9.20040968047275,-41.2843298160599));
#485=CARTESIAN_POINT('',(14.0473575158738,9.48361362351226,-41.3345560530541));
#486=CARTESIAN_POINT('',(13.9820072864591,9.6234377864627,-41.3566871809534));
#487=CARTESIAN_POINT('',(13.8629979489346,9.90855539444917,-41.3967317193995));
#488=CARTESIAN_POINT('',(13.8093381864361,10.0538485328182,-41.4146453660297));
#489=CARTESIAN_POINT('',(13.7142455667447,10.3488016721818,-41.4462319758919));
#490=CARTESIAN_POINT('',(13.6728104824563,10.4984608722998,-41.4599057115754));
#491=CARTESIAN_POINT('',(13.6025661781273,10.8010357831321,-41.4830052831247));
#492=CARTESIAN_POINT('',(13.5737567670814,10.9539514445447,-41.4924311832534));
#493=CARTESIAN_POINT('',(13.5298518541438,11.2563426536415,-41.5067679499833));
#494=CARTESIAN_POINT('',(13.5143023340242,11.4057453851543,-41.5118283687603));
#495=CARTESIAN_POINT('',(13.4953490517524,11.7054530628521,-41.5179939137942));
#496=CARTESIAN_POINT('',(13.4919493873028,11.8557582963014,-41.5190977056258));
#497=CARTESIAN_POINT('',(13.4973382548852,12.1560584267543,-41.5173461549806));
#498=CARTESIAN_POINT('',(13.50612128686,12.3060534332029,-41.5144925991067));
#499=CARTESIAN_POINT('',(13.5357892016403,12.604769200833,-41.5048288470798));
#500=CARTESIAN_POINT('',(13.5566785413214,12.7534894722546,-41.4980171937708));
#501=CARTESIAN_POINT('',(13.6100836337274,13.0469666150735,-41.4805323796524));
#502=CARTESIAN_POINT('',(13.6424742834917,13.1917487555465,-41.4699007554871));
#503=CARTESIAN_POINT('',(13.7186346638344,13.4780008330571,-41.4447684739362));
#504=CARTESIAN_POINT('',(13.7624085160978,13.6194695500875,-41.4302664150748));
#505=CARTESIAN_POINT('',(13.8609149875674,13.8980143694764,-41.3974140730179));
#506=CARTESIAN_POINT('',(13.9156433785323,14.0350921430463,-41.3790652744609));
#507=CARTESIAN_POINT('',(14.0356017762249,14.3040436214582,-41.3385298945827));
#508=CARTESIAN_POINT('',(14.1008356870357,14.4359153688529,-41.3163418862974));
#509=CARTESIAN_POINT('',(14.2419201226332,14.694840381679,-41.2679232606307));
#510=CARTESIAN_POINT('',(14.3178707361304,14.821831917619,-41.2416542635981));
#511=CARTESIAN_POINT('',(14.4792383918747,15.0688156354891,-41.1852779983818));
#512=CARTESIAN_POINT('',(14.5646588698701,15.188805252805,-41.1551693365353));
#513=CARTESIAN_POINT('',(14.7441756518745,15.420978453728,-41.091197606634));
#514=CARTESIAN_POINT('',(14.8382692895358,15.5331644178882,-41.0573356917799));
#515=CARTESIAN_POINT('',(15.034393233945,15.749179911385,-40.9859253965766));
#516=CARTESIAN_POINT('',(15.1364265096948,15.8530062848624,-40.9483756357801));
#517=CARTESIAN_POINT('',(15.3510355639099,16.0549828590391,-40.8684155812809));
#518=CARTESIAN_POINT('',(15.4638471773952,16.1528357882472,-40.8258863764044));
#519=CARTESIAN_POINT('',(15.6960831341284,16.3385517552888,-40.737165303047));
#520=CARTESIAN_POINT('',(15.8155098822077,16.4264111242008,-40.6909720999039));
#521=CARTESIAN_POINT('',(16.182235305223,16.674346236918,-40.5471586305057));
#522=CARTESIAN_POINT('',(16.4381493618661,16.8189377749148,-40.44424169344));
#523=CARTESIAN_POINT('',(16.980709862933,17.071999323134,-40.2195841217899));
#524=CARTESIAN_POINT('',(17.268278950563,17.1777896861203,-40.0970855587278));
#525=CARTESIAN_POINT('',(17.8520462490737,17.340278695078,-39.8406115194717));
#526=CARTESIAN_POINT('',(18.1482475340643,17.3969596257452,-39.706631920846));
#527=CARTESIAN_POINT('',(18.7662236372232,17.4646480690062,-39.4185548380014));
#528=CARTESIAN_POINT('',(19.0881006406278,17.4715216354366,-39.2637088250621));
#529=CARTESIAN_POINT('',(19.7251192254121,17.4305668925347,-38.9475858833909));
#530=CARTESIAN_POINT('',(20.0402588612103,17.3827229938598,-38.7863071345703));
#531=CARTESIAN_POINT('',(20.6809032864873,17.2287487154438,-38.4487907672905));
#532=CARTESIAN_POINT('',(21.0052868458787,17.1183468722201,-38.2723708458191));
#533=CARTESIAN_POINT('',(21.6304179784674,16.8388580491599,-37.9225720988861));
#534=CARTESIAN_POINT('',(21.9311357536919,16.6696984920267,-37.7491973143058));
#535=CARTESIAN_POINT('',(22.360718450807,16.3719415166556,-37.4952694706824));
#536=CARTESIAN_POINT('',(22.5017904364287,16.2638781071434,-37.410734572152));
#537=CARTESIAN_POINT('',(22.7742875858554,16.0334059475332,-37.2454735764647));
#538=CARTESIAN_POINT('',(22.9057102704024,15.9109935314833,-37.16474846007));
#539=CARTESIAN_POINT('',(23.1570581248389,15.652762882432,-37.0086566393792));
#540=CARTESIAN_POINT('',(23.277021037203,15.5169918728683,-36.933272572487));
#541=CARTESIAN_POINT('',(23.5044548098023,15.2323397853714,-36.7889504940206));
#542=CARTESIAN_POINT('',(23.6119374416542,15.0834712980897,-36.7200064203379));
#543=CARTESIAN_POINT('',(23.7510170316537,14.8689176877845,-36.6300351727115));
#544=CARTESIAN_POINT('',(23.7885961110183,14.808442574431,-36.6056383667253));
#545=CARTESIAN_POINT('',(23.8615761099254,14.6857707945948,-36.5581077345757));
#546=CARTESIAN_POINT('',(23.8969785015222,14.623575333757,-36.5349730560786));
#547=CARTESIAN_POINT('',(23.9312663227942,14.5605207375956,-36.5125));
#548=B_SPLINE_CURVE_WITH_KNOTS('',3,(#446,#447,#448,#449,#450,#451,#452,#453,#454,#455,#456,
#457,#458,#459,#460,#461,#462,#463,#464,#465,#466,#467,#468,#469,#470,#471,#472,#473,#474,#475,
#476,#477,#478,#479,#480,#481,#482,#483,#484,#485,#486,#487,#488,#489,#490,#491,#492,#493,#494,
#495,#496,#497,#498,#499,#500,#501,#502,#503,#504,#505,#506,#507,#508,#509,#510,#511,#512,#513,
#514,#515,#516,#517,#518,#519,#520,#521,#522,#523,#524,#525,#526,#527,#528,#529,#530,#531,#532,
#533,#534,#535,#536,#537,#538,#539,#540,#541,#542,#543,#544,#545,#546,#547),.UNSPECIFIED.,.F.,
.F.,(4,2,2,2,2,2,2,2,2,2,2,2,2,2,2,2,2,2,2,2,2,2,2,2,2,2,2,2,2,2,2,2,2,2,2,2,2,2,2,2,2,2,2,2,2,
2,2,2,2,2,4),(0.,0.5201551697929,1.03982618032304,2.07367689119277,3.10390226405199,
4.13567968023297,5.28122182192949,6.42677965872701,7.01561551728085,7.60419711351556,
8.19294783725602,8.78138426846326,9.33327836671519,9.88489953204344,10.4363868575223,
10.9878246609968,11.4895275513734,11.9911882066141,12.4926894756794,12.9941670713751,
13.4613493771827,13.9285055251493,14.3955765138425,14.8626404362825,15.3129841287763,
15.7634796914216,16.2137719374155,16.6642300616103,17.1099314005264,17.5557943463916,
18.00148552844,18.447342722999,18.8976798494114,19.3481809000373,19.79854391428,
20.2490761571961,20.7143639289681,21.1798219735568,22.1100230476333,23.0958939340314,
24.0821203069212,25.1493536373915,26.2168911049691,27.3680368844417,28.5206096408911,
29.110319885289,29.7001811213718,30.2880273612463,30.8753145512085,31.1010560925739,
31.3266432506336),.UNSPECIFIED.);
#549=CARTESIAN_POINT('',(23.9312663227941,9.25197926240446,-36.5125));
#550=VERTEX_POINT('',#549);
#551=CARTESIAN_POINT('',(23.9312663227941,14.5605207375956,-36.5125));
#552=VERTEX_POINT('',#551);
#553=EDGE_CURVE('E11',#550,#552,#548,.T.);
#554=ORIENTED_EDGE('',*,*,#553,.F.);
#555=DIRECTION('',(0.,-1.,0.));
#556=VECTOR('',#555,1.);
#557=CARTESIAN_POINT('',(23.9312663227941,19.05,-36.5125));
#558=LINE('',#557,#556);
#559=EDGE_CURVE('E99',#552,#550,#558,.T.);
#560=ORIENTED_EDGE('',*,*,#559,.F.);
#561=EDGE_LOOP('',(#554,#560));
#562=FACE_BOUND('',#561,.T.);
#563=ADVANCED_FACE('F32',(#140,#257,#317,#328,#445,#562),#23,.T.);
#564=CARTESIAN_POINT('',(19.05,11.90625,-43.65625));
#565=DIRECTION('',(0.,0.,1.));
#566=DIRECTION('',(1.,0.,0.));
#567=AXIS2_PLACEMENT_3D('',#564,#565,#566);
#568=CYLINDRICAL_SURFACE('',#567,3.96875);
#569=CARTESIAN_POINT('',(19.05,11.90625,-19.84375));
#570=DIRECTION('',(0.,0.,-1.));
#571=DIRECTION('',(0.,1.,0.));
#572=AXIS2_PLACEMENT_3D('',#569,#570,#571);
#573=CIRCLE('',#572,3.96875);
#574=CARTESIAN_POINT('',(19.05,15.875,-19.84375));
#575=VERTEX_POINT('',#574);
#576=EDGE_CURVE('E103',#575,#575,#573,.F.);
#577=ORIENTED_EDGE('',*,*,#576,.T.);
#578=EDGE_LOOP('',(#577));
#579=FACE_BOUND('',#578,.T.);
#580=CARTESIAN_POINT('',(19.05,11.90625,-36.5125));
#581=DIRECTION('',(0.,0.,-1.));
#582=DIRECTION('',(-1.,0.,0.));
#583=AXIS2_PLACEMENT_3D('',#580,#581,#582);
#584=CIRCLE('',#583,3.96875);
#585=CARTESIAN_POINT('',(15.08125,11.90625,-36.5125));
#586=VERTEX_POINT('',#585);
#587=EDGE_CURVE('E104',#586,#586,#584,.T.);
#588=ORIENTED_EDGE('',*,*,#587,.T.);
#589=EDGE_LOOP('',(#588));
#590=FACE_BOUND('',#589,.T.);
#591=ADVANCED_FACE('F110',(#579,#590),#568,.F.);
#592=CARTESIAN_POINT('',(-43.65625,6.35,-19.84375));
#593=DIRECTION('',(0.,0.,-1.));
#594=DIRECTION('',(0.,1.,0.));
#595=AXIS2_PLACEMENT_3D('',#592,#593,#594);
#596=PLANE('',#595);
#597=DIRECTION('',(-1.,0.,0.));
#598=VECTOR('',#597,1.);
#599=CARTESIAN_POINT('',(0.,19.05,-19.84375));
#600=LINE('',#599,#598);
#601=EDGE_CURVE('E206',#307,#303,#600,.T.);
#602=ORIENTED_EDGE('',*,*,#601,.T.);
#603=ORIENTED_EDGE('',*,*,#304,.F.);
#604=DIRECTION('',(1.,0.,0.));
#605=VECTOR('',#604,1.);
#606=CARTESIAN_POINT('',(-43.65625,6.35,-19.84375));
#607=LINE('',#606,#605);
#608=EDGE_CURVE('E221',#295,#266,#607,.T.);
#609=ORIENTED_EDGE('',*,*,#608,.T.);
#610=ORIENTED_EDGE('',*,*,#314,.F.);
#611=EDGE_LOOP('',(#602,#603,#609,#610));
#612=FACE_BOUND('',#611,.T.);
#613=CARTESIAN_POINT('',(-19.05,11.90625,-19.84375));
#614=DIRECTION('',(0.,0.,-1.));
#615=DIRECTION('',(0.,1.,0.));
#616=AXIS2_PLACEMENT_3D('',#613,#614,#615);
#617=CIRCLE('',#616,3.96875);
#618=CARTESIAN_POINT('',(-19.05,15.875,-19.84375));
#619=VERTEX_POINT('',#618);
#620=EDGE_CURVE('E258',#619,#619,#617,.T.);
#621=ORIENTED_EDGE('',*,*,#620,.T.);
#622=EDGE_LOOP('',(#621));
#623=FACE_BOUND('',#622,.T.);
#624=ORIENTED_EDGE('',*,*,#576,.F.);
#625=EDGE_LOOP('',(#624));
#626=FACE_BOUND('',#625,.T.);
#627=ADVANCED_FACE('F115',(#612,#623,#626),#596,.F.);
#628=CARTESIAN_POINT('',(-19.05,11.90625,-43.65625));
#629=DIRECTION('',(0.,0.,1.));
#630=DIRECTION('',(1.,0.,0.));
#631=AXIS2_PLACEMENT_3D('',#628,#629,#630);
#632=CYLINDRICAL_SURFACE('',#631,3.96875);
#633=ORIENTED_EDGE('',*,*,#620,.F.);
#634=EDGE_LOOP('',(#633));
#635=FACE_BOUND('',#634,.T.);
#636=CARTESIAN_POINT('',(-19.05,11.90625,-36.5125));
#637=DIRECTION('',(0.,0.,-1.));
#638=DIRECTION('',(-1.,0.,0.));
#639=AXIS2_PLACEMENT_3D('',#636,#637,#638);
#640=CIRCLE('',#639,3.96875);
#641=CARTESIAN_POINT('',(-23.01875,11.90625,-36.5125));
#642=VERTEX_POINT('',#641);
#643=EDGE_CURVE('E262',#642,#642,#640,.F.);
#644=ORIENTED_EDGE('',*,*,#643,.F.);
#645=EDGE_LOOP('',(#644));
#646=FACE_BOUND('',#645,.T.);
#647=ADVANCED_FACE('F174',(#635,#646),#632,.F.);
#648=CARTESIAN_POINT('',(19.05,11.90625,43.65625));
#649=DIRECTION('',(0.,0.,-1.));
#650=DIRECTION('',(-1.,0.,0.));
#651=AXIS2_PLACEMENT_3D('',#648,#649,#650);
#652=CYLINDRICAL_SURFACE('',#651,3.96875);
#653=CARTESIAN_POINT('',(19.05,11.90625,19.84375));
#654=DIRECTION('',(0.,0.,1.));
#655=DIRECTION('',(0.,-1.,0.));
#656=AXIS2_PLACEMENT_3D('',#653,#654,#655);
#657=CIRCLE('',#656,3.96875);
#658=CARTESIAN_POINT('',(19.05,7.93750000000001,19.84375));
#659=VERTEX_POINT('',#658);
#660=EDGE_CURVE('E156',#659,#659,#657,.T.);
#661=ORIENTED_EDGE('',*,*,#660,.F.);
#662=EDGE_LOOP('',(#661));
#663=FACE_BOUND('',#662,.T.);
#664=CARTESIAN_POINT('',(19.05,11.90625,36.5125));
#665=DIRECTION('',(0.,0.,1.));
#666=DIRECTION('',(1.,0.,0.));
#667=AXIS2_PLACEMENT_3D('',#664,#665,#666);
#668=CIRCLE('',#667,3.96875);
#669=CARTESIAN_POINT('',(23.01875,11.90625,36.5125));
#670=VERTEX_POINT('',#669);
#671=EDGE_CURVE('E306',#670,#670,#668,.F.);
#672=ORIENTED_EDGE('',*,*,#671,.F.);
#673=EDGE_LOOP('',(#672));
#674=FACE_BOUND('',#673,.T.);
#675=ADVANCED_FACE('F170',(#663,#674),#652,.F.);
#676=CARTESIAN_POINT('',(-19.05,11.90625,43.65625));
#677=DIRECTION('',(0.,0.,-1.));
#678=DIRECTION('',(-1.,0.,0.));
#679=AXIS2_PLACEMENT_3D('',#676,#677,#678);
#680=CYLINDRICAL_SURFACE('',#679,3.96875);
#681=CARTESIAN_POINT('',(-19.05,11.90625,19.84375));
#682=DIRECTION('',(0.,0.,1.));
#683=DIRECTION('',(0.,-1.,0.));
#684=AXIS2_PLACEMENT_3D('',#681,#682,#683);
#685=CIRCLE('',#684,3.96875);
#686=CARTESIAN_POINT('',(-19.05,7.93750000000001,19.84375));
#687=VERTEX_POINT('',#686);
#688=EDGE_CURVE('E216',#687,#687,#685,.F.);
#689=ORIENTED_EDGE('',*,*,#688,.T.);
#690=EDGE_LOOP('',(#689));
#691=FACE_BOUND('',#690,.T.);
#692=CARTESIAN_POINT('',(-19.05,11.90625,36.5125));
#693=DIRECTION('',(0.,0.,1.));
#694=DIRECTION('',(1.,0.,0.));
#695=AXIS2_PLACEMENT_3D('',#692,#693,#694);
#696=CIRCLE('',#695,3.96875);
#697=CARTESIAN_POINT('',(-15.08125,11.90625,36.5125));
#698=VERTEX_POINT('',#697);
#699=EDGE_CURVE('E154',#698,#698,#696,.T.);
#700=ORIENTED_EDGE('',*,*,#699,.T.);
#701=EDGE_LOOP('',(#700));
#702=FACE_BOUND('',#701,.T.);
#703=ADVANCED_FACE('F166',(#691,#702),#680,.F.);
#704=CARTESIAN_POINT('',(-43.65625,19.05,19.84375));
#705=DIRECTION('',(0.,0.,1.));
#706=DIRECTION('',(0.,-1.,0.));
#707=AXIS2_PLACEMENT_3D('',#704,#705,#706);
#708=PLANE('',#707);
#709=ORIENTED_EDGE('',*,*,#660,.T.);
#710=EDGE_LOOP('',(#709));
#711=FACE_BOUND('',#710,.T.);
#712=DIRECTION('',(1.,0.,0.));
#713=VECTOR('',#712,1.);
#714=CARTESIAN_POINT('',(0.,19.05,19.84375));
#715=LINE('',#714,#713);
#716=EDGE_CURVE('E209',#283,#274,#715,.T.);
#717=ORIENTED_EDGE('',*,*,#716,.T.);
#718=ORIENTED_EDGE('',*,*,#275,.F.);
#719=DIRECTION('',(1.,0.,0.));
#720=VECTOR('',#719,1.);
#721=CARTESIAN_POINT('',(-43.65625,6.35,19.84375));
#722=LINE('',#721,#720);
#723=EDGE_CURVE('E218',#291,#264,#722,.T.);
#724=ORIENTED_EDGE('',*,*,#723,.F.);
#725=ORIENTED_EDGE('',*,*,#292,.F.);
#726=EDGE_LOOP('',(#717,#718,#724,#725));
#727=FACE_BOUND('',#726,.T.);
#728=ORIENTED_EDGE('',*,*,#688,.F.);
#729=EDGE_LOOP('',(#728));
#730=FACE_BOUND('',#729,.T.);
#731=ADVANCED_FACE('F169',(#711,#727,#730),#708,.F.);
#732=CARTESIAN_POINT('',(0.,19.05,0.));
#733=DIRECTION('',(0.,1.,0.));
#734=DIRECTION('',(0.,0.,1.));
#735=AXIS2_PLACEMENT_3D('',#732,#733,#734);
#736=PLANE('',#735);
#737=ORIENTED_EDGE('',*,*,#716,.F.);
#738=ORIENTED_EDGE('',*,*,#284,.T.);
#739=EDGE_LOOP('',(#737,#738));
#740=FACE_BOUND('',#739,.T.);
#741=ADVANCED_FACE('F182',(#740),#736,.T.);
#742=CARTESIAN_POINT('',(0.,0.,0.));
#743=DIRECTION('',(0.,1.,0.));
#744=DIRECTION('',(0.,0.,1.));
#745=AXIS2_PLACEMENT_3D('',#742,#743,#744);
#746=PLANE('',#745);
#747=ORIENTED_EDGE('',*,*,#325,.F.);
#748=EDGE_LOOP('',(#747));
#749=FACE_BOUND('',#748,.T.);
#750=CARTESIAN_POINT('',(0.,0.,0.));
#751=DIRECTION('',(0.,1.,0.));
#752=DIRECTION('',(0.,0.,1.));
#753=AXIS2_PLACEMENT_3D('',#750,#751,#752);
#754=CIRCLE('',#753,25.3619);
#755=CARTESIAN_POINT('',(0.,0.,25.3619));
#756=VERTEX_POINT('',#755);
#757=EDGE_CURVE('E204',#756,#756,#754,.F.);
#758=ORIENTED_EDGE('',*,*,#757,.F.);
#759=EDGE_LOOP('',(#758));
#760=FACE_BOUND('',#759,.T.);
#761=ADVANCED_FACE('F193',(#749,#760),#746,.F.);
#762=ORIENTED_EDGE('',*,*,#601,.F.);
#763=ORIENTED_EDGE('',*,*,#308,.T.);
#764=EDGE_LOOP('',(#762,#763));
#765=FACE_BOUND('',#764,.T.);
#766=ADVANCED_FACE('F190',(#765),#736,.T.);
#767=CARTESIAN_POINT('',(0.,-13.49375,0.));
#768=DIRECTION('',(0.,1.,0.));
#769=DIRECTION('',(0.,0.,1.));
#770=AXIS2_PLACEMENT_3D('',#767,#768,#769);
#771=CYLINDRICAL_SURFACE('',#770,25.3619);
#772=CARTESIAN_POINT('',(0.,-13.49375,0.));
#773=DIRECTION('',(0.,-1.,0.));
#774=DIRECTION('',(0.,0.,-1.));
#775=AXIS2_PLACEMENT_3D('',#772,#773,#774);
#776=CIRCLE('',#775,25.3619);
#777=CARTESIAN_POINT('',(0.,-13.49375,-25.3619));
#778=VERTEX_POINT('',#777);
#779=EDGE_CURVE('E242',#778,#778,#776,.T.);
#780=ORIENTED_EDGE('',*,*,#779,.F.);
#781=EDGE_LOOP('',(#780));
#782=FACE_BOUND('',#781,.T.);
#783=ORIENTED_EDGE('',*,*,#757,.T.);
#784=EDGE_LOOP('',(#783));
#785=FACE_BOUND('',#784,.T.);
#786=ADVANCED_FACE('F186',(#782,#785),#771,.T.);
#787=CARTESIAN_POINT('',(0.,-13.49375,0.));
#788=DIRECTION('',(0.,-1.,0.));
#789=DIRECTION('',(0.,0.,-1.));
#790=AXIS2_PLACEMENT_3D('',#787,#788,#789);
#791=PLANE('',#790);
#792=ORIENTED_EDGE('',*,*,#779,.T.);
#793=EDGE_LOOP('',(#792));
#794=FACE_BOUND('',#793,.T.);
#795=ADVANCED_FACE('F178',(#794),#791,.T.);
#796=CARTESIAN_POINT('',(-43.65625,6.35,-19.84375));
#797=DIRECTION('',(0.,1.,0.));
#798=DIRECTION('',(0.,0.,1.));
#799=AXIS2_PLACEMENT_3D('',#796,#797,#798);
#800=PLANE('',#799);
#801=ORIENTED_EDGE('',*,*,#723,.T.);
#802=ORIENTED_EDGE('',*,*,#267,.T.);
#803=ORIENTED_EDGE('',*,*,#608,.F.);
#804=ORIENTED_EDGE('',*,*,#296,.T.);
#805=EDGE_LOOP('',(#801,#802,#803,#804));
#806=FACE_BOUND('',#805,.T.);
#807=ADVANCED_FACE('F164',(#806),#800,.T.);
#808=CARTESIAN_POINT('',(-19.05,11.90625,43.65625));
#809=DIRECTION('',(0.,0.,-1.));
#810=DIRECTION('',(-1.,0.,0.));
#811=AXIS2_PLACEMENT_3D('',#808,#809,#810);
#812=CYLINDRICAL_SURFACE('',#811,5.55625);
#813=ORIENTED_EDGE('',*,*,#436,.T.);
#814=CARTESIAN_POINT('',(-19.05,11.90625,36.5125));
#815=DIRECTION('',(0.,0.,1.));
#816=DIRECTION('',(1.,0.,0.));
#817=AXIS2_PLACEMENT_3D('',#814,#815,#816);
#818=CIRCLE('',#817,5.55625);
#819=EDGE_CURVE('E226',#433,#435,#818,.T.);
#820=ORIENTED_EDGE('',*,*,#819,.F.);
#821=EDGE_LOOP('',(#813,#820));
#822=FACE_BOUND('',#821,.T.);
#823=ADVANCED_FACE('F158',(#822),#812,.F.);
#824=CARTESIAN_POINT('',(-19.05,11.90625,36.5125));
#825=DIRECTION('',(0.,0.,1.));
#826=DIRECTION('',(1.,0.,0.));
#827=AXIS2_PLACEMENT_3D('',#824,#825,#826);
#828=PLANE('',#827);
#829=ORIENTED_EDGE('',*,*,#699,.F.);
#830=EDGE_LOOP('',(#829));
#831=FACE_BOUND('',#830,.T.);
#832=ORIENTED_EDGE('',*,*,#442,.T.);
#833=ORIENTED_EDGE('',*,*,#819,.T.);
#834=EDGE_LOOP('',(#832,#833));
#835=FACE_BOUND('',#834,.T.);
#836=ADVANCED_FACE('F163',(#831,#835),#828,.T.);
#837=CARTESIAN_POINT('',(19.05,11.90625,43.65625));
#838=DIRECTION('',(0.,0.,-1.));
#839=DIRECTION('',(-1.,0.,0.));
#840=AXIS2_PLACEMENT_3D('',#837,#838,#839);
#841=CYLINDRICAL_SURFACE('',#840,5.55625);
#842=CARTESIAN_POINT('',(19.05,11.90625,36.5125));
#843=DIRECTION('',(0.,0.,-1.));
#844=DIRECTION('',(-1.,0.,0.));
#845=AXIS2_PLACEMENT_3D('',#842,#843,#844);
#846=CIRCLE('',#845,5.55625);
#847=EDGE_CURVE('E307',#146,#148,#846,.T.);
#848=ORIENTED_EDGE('',*,*,#847,.T.);
#849=ORIENTED_EDGE('',*,*,#254,.F.);
#850=EDGE_LOOP('',(#848,#849));
#851=FACE_BOUND('',#850,.T.);
#852=ADVANCED_FACE('F296',(#851),#841,.F.);
#853=CARTESIAN_POINT('',(19.05,11.90625,36.5125));
#854=DIRECTION('',(0.,0.,1.));
#855=DIRECTION('',(-1.,0.,0.));
#856=AXIS2_PLACEMENT_3D('',#853,#854,#855);
#857=PLANE('',#856);
#858=ORIENTED_EDGE('',*,*,#671,.T.);
#859=EDGE_LOOP('',(#858));
#860=FACE_BOUND('',#859,.T.);
#861=ORIENTED_EDGE('',*,*,#149,.T.);
#862=ORIENTED_EDGE('',*,*,#847,.F.);
#863=EDGE_LOOP('',(#861,#862));
#864=FACE_BOUND('',#863,.T.);
#865=ADVANCED_FACE('F289',(#860,#864),#857,.T.);
#866=CARTESIAN_POINT('',(-19.05,11.90625,-43.65625));
#867=DIRECTION('',(0.,0.,1.));
#868=DIRECTION('',(1.,0.,0.));
#869=AXIS2_PLACEMENT_3D('',#866,#867,#868);
#870=CYLINDRICAL_SURFACE('',#869,5.55625);
#871=CARTESIAN_POINT('',(-19.05,11.90625,-36.5125));
#872=DIRECTION('',(0.,0.,1.));
#873=DIRECTION('',(1.,0.,0.));
#874=AXIS2_PLACEMENT_3D('',#871,#872,#873);
#875=CIRCLE('',#874,5.55625);
#876=EDGE_CURVE('E57',#29,#31,#875,.T.);
#877=ORIENTED_EDGE('',*,*,#876,.T.);
#878=ORIENTED_EDGE('',*,*,#137,.F.);
#879=EDGE_LOOP('',(#877,#878));
#880=FACE_BOUND('',#879,.T.);
#881=ADVANCED_FACE('F284',(#880),#870,.F.);
#882=CARTESIAN_POINT('',(-19.05,11.90625,-36.5125));
#883=DIRECTION('',(0.,0.,-1.));
#884=DIRECTION('',(1.,0.,0.));
#885=AXIS2_PLACEMENT_3D('',#882,#883,#884);
#886=PLANE('',#885);
#887=ORIENTED_EDGE('',*,*,#643,.T.);
#888=EDGE_LOOP('',(#887));
#889=FACE_BOUND('',#888,.T.);
#890=ORIENTED_EDGE('',*,*,#32,.T.);
#891=ORIENTED_EDGE('',*,*,#876,.F.);
#892=EDGE_LOOP('',(#890,#891));
#893=FACE_BOUND('',#892,.T.);
#894=ADVANCED_FACE('F280',(#889,#893),#886,.T.);
#895=CARTESIAN_POINT('',(19.05,11.90625,-43.65625));
#896=DIRECTION('',(0.,0.,1.));
#897=DIRECTION('',(1.,0.,0.));
#898=AXIS2_PLACEMENT_3D('',#895,#896,#897);
#899=CYLINDRICAL_SURFACE('',#898,5.55625);
#900=ORIENTED_EDGE('',*,*,#553,.T.);
#901=CARTESIAN_POINT('',(19.05,11.90625,-36.5125));
#902=DIRECTION('',(0.,0.,-1.));
#903=DIRECTION('',(-1.,0.,0.));
#904=AXIS2_PLACEMENT_3D('',#901,#902,#903);
#905=CIRCLE('',#904,5.55625);
#906=EDGE_CURVE('E51',#550,#552,#905,.T.);
#907=ORIENTED_EDGE('',*,*,#906,.F.);
#908=EDGE_LOOP('',(#900,#907));
#909=FACE_BOUND('',#908,.T.);
#910=ADVANCED_FACE('F107',(#909),#899,.F.);
#911=CARTESIAN_POINT('',(19.05,11.90625,-36.5125));
#912=DIRECTION('',(0.,0.,-1.));
#913=DIRECTION('',(-1.,0.,0.));
#914=AXIS2_PLACEMENT_3D('',#911,#912,#913);
#915=PLANE('',#914);
#916=ORIENTED_EDGE('',*,*,#587,.F.);
#917=EDGE_LOOP('',(#916));
#918=FACE_BOUND('',#917,.T.);
#919=ORIENTED_EDGE('',*,*,#559,.T.);
#920=ORIENTED_EDGE('',*,*,#906,.T.);
#921=EDGE_LOOP('',(#919,#920));
#922=FACE_BOUND('',#921,.T.);
#923=ADVANCED_FACE('F100',(#918,#922),#915,.T.);
#924=CLOSED_SHELL('',(#563,#591,#627,#647,#675,#703,#731,#741,#761,#766,#786,#795,#807,#823,
#836,#852,#865,#881,#894,#910,#923));
#925=MANIFOLD_SOLID_BREP('B2',#924);
#926=ADVANCED_BREP_SHAPE_REPRESENTATION('',(#18,#925),#14);
#927=SHAPE_DEFINITION_REPRESENTATION(#9,#926);
ENDSEC;
END-ISO-10303-21;
